VERSION 5.8 ;
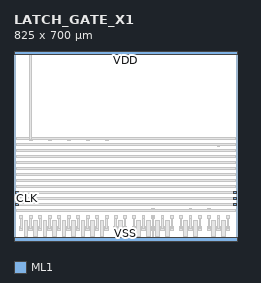
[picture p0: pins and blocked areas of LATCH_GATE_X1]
MACRO LATCH_GATE_X1
  CLASS CORE ;
  ORIGIN 0 0 ;
  SIZE 825 BY 700 ;
  SITE ICPS2023_5_ROW700 ;
  PIN D
    DIRECTION INPUT ;
    USE SIGNAL ;
    PORT
      LAYER ML1 ;
        RECT 5 130 15 140 ;
        RECT 810 130 820 140 ;
    END
  END D
  PIN CLK
    DIRECTION INPUT ;
    USE SIGNAL ;
    PORT
      LAYER ML1 ;
        RECT 5 152 15 162 ;
        RECT 810 152 820 162 ;
    END
  END CLK
  PIN Q
    DIRECTION OUTPUT ;
    USE SIGNAL ;
    PORT
      LAYER ML1 ;
        RECT 5 174 15 184 ;
        RECT 810 174 820 184 ;
    END
  END Q
  PIN VDD
    DIRECTION INOUT ;
    USE POWER ;
    PORT
      LAYER ML1 ;
        RECT 0 688 825 700 ;
    END
  END VDD
  PIN VSS
    DIRECTION INOUT ;
    USE GROUND ;
    PORT
      LAYER ML1 ;
        RECT 0 0 825 12 ;
    END
  END VSS
  OBS
    LAYER ML1 ;
      RECT 20 39.5 33 52.5 ;
      RECT 55 39.5 68 52.5 ;
      RECT 90 39.5 103 52.5 ;
      RECT 125 39.5 138 52.5 ;
      RECT 160 39.5 173 52.5 ;
      RECT 195 39.5 208 52.5 ;
      RECT 230 39.5 243 52.5 ;
      RECT 265 39.5 278 52.5 ;
      RECT 300 39.5 313 52.5 ;
      RECT 335 39.5 348 52.5 ;
      RECT 37.5 16 50.5 29 ;
      RECT 37.5 63 50.5 76 ;
      RECT 37 16 51 76 ;
      RECT 72.5 16 85.5 29 ;
      RECT 72.5 63 85.5 76 ;
      RECT 72 16 86 76 ;
      RECT 107.5 16 120.5 29 ;
      RECT 107.5 63 120.5 76 ;
      RECT 107 16 121 76 ;
      RECT 142.5 16 155.5 29 ;
      RECT 142.5 63 155.5 76 ;
      RECT 142 16 156 76 ;
      RECT 177.5 16 190.5 29 ;
      RECT 177.5 63 190.5 76 ;
      RECT 177 16 191 76 ;
      RECT 212.5 16 225.5 29 ;
      RECT 212.5 63 225.5 76 ;
      RECT 212 16 226 76 ;
      RECT 247.5 16 260.5 29 ;
      RECT 247.5 63 260.5 76 ;
      RECT 247 16 261 76 ;
      RECT 282.5 16 295.5 29 ;
      RECT 282.5 63 295.5 76 ;
      RECT 282 16 296 76 ;
      RECT 317.5 16 330.5 29 ;
      RECT 317.5 63 330.5 76 ;
      RECT 317 16 331 76 ;
      RECT 23.5 46 29.5 89 ;
      RECT 21.5 84 31.5 94 ;
      RECT 21.5 240 31.5 250 ;
      RECT 58.5 46 64.5 89 ;
      RECT 56.5 84 66.5 94 ;
      RECT 56.5 372 66.5 382 ;
      RECT 93.5 46 99.5 89 ;
      RECT 91.5 84 101.5 94 ;
      RECT 91.5 262 101.5 272 ;
      RECT 128.5 46 134.5 89 ;
      RECT 126.5 84 136.5 94 ;
      RECT 126.5 372 136.5 382 ;
      RECT 163.5 46 169.5 89 ;
      RECT 161.5 84 171.5 94 ;
      RECT 161.5 174 171.5 184 ;
      RECT 198.5 46 204.5 89 ;
      RECT 196.5 84 206.5 94 ;
      RECT 196.5 372 206.5 382 ;
      RECT 233.5 46 239.5 89 ;
      RECT 231.5 84 241.5 94 ;
      RECT 231.5 284 241.5 294 ;
      RECT 268.5 46 274.5 89 ;
      RECT 266.5 84 276.5 94 ;
      RECT 266.5 372 276.5 382 ;
      RECT 303.5 46 309.5 89 ;
      RECT 301.5 84 311.5 94 ;
      RECT 301.5 328 311.5 338 ;
      RECT 338.5 46 344.5 89 ;
      RECT 336.5 84 346.5 94 ;
      RECT 336.5 372 346.5 382 ;
      RECT 39 130 49 140 ;
      RECT 74 284 84 294 ;
      RECT 109 174 119 184 ;
      RECT 144 328 154 338 ;
      RECT 179 262 189 272 ;
      RECT 214 240 224 250 ;
      RECT 249 152 259 162 ;
      RECT 284 130 294 140 ;
      RECT 319 152 329 162 ;
      RECT 368 39.5 381 52.5 ;
      RECT 403 39.5 416 52.5 ;
      RECT 385.5 16 398.5 29 ;
      RECT 385.5 63 398.5 76 ;
      RECT 385 16 399 76 ;
      RECT 371.5 46 377.5 89 ;
      RECT 369.5 84 379.5 94 ;
      RECT 369.5 196 379.5 206 ;
      RECT 406.5 46 412.5 89 ;
      RECT 404.5 84 414.5 94 ;
      RECT 404.5 262 414.5 272 ;
      RECT 387 284 397 294 ;
      RECT 436 39.5 449 52.5 ;
      RECT 471 39.5 484 52.5 ;
      RECT 506 39.5 519 52.5 ;
      RECT 541 39.5 554 52.5 ;
      RECT 576 39.5 589 52.5 ;
      RECT 453.5 16 466.5 29 ;
      RECT 453.5 63 466.5 76 ;
      RECT 453 16 467 76 ;
      RECT 488.5 16 501.5 29 ;
      RECT 488.5 63 501.5 76 ;
      RECT 488 16 502 76 ;
      RECT 523.5 16 536.5 29 ;
      RECT 523.5 63 536.5 76 ;
      RECT 523 16 537 76 ;
      RECT 558.5 16 571.5 29 ;
      RECT 558.5 63 571.5 76 ;
      RECT 558 16 572 76 ;
      RECT 439.5 46 445.5 89 ;
      RECT 437.5 84 447.5 94 ;
      RECT 437.5 284 447.5 294 ;
      RECT 474.5 46 480.5 89 ;
      RECT 472.5 84 482.5 94 ;
      RECT 472.5 306 482.5 316 ;
      RECT 509.5 46 515.5 89 ;
      RECT 507.5 84 517.5 94 ;
      RECT 507.5 108 517.5 118 ;
      RECT 544.5 46 550.5 89 ;
      RECT 542.5 84 552.5 94 ;
      RECT 542.5 218 552.5 228 ;
      RECT 579.5 46 585.5 89 ;
      RECT 577.5 84 587.5 94 ;
      RECT 577.5 174 587.5 184 ;
      RECT 455 240 465 250 ;
      RECT 490 152 500 162 ;
      RECT 525 262 535 272 ;
      RECT 560 328 570 338 ;
      RECT 609 39.5 622 52.5 ;
      RECT 644 39.5 657 52.5 ;
      RECT 679 39.5 692 52.5 ;
      RECT 626.5 16 639.5 29 ;
      RECT 626.5 63 639.5 76 ;
      RECT 626 16 640 76 ;
      RECT 661.5 16 674.5 29 ;
      RECT 661.5 63 674.5 76 ;
      RECT 661 16 675 76 ;
      RECT 612.5 46 618.5 89 ;
      RECT 610.5 84 620.5 94 ;
      RECT 610.5 196 620.5 206 ;
      RECT 647.5 46 653.5 89 ;
      RECT 645.5 84 655.5 94 ;
      RECT 645.5 108 655.5 118 ;
      RECT 682.5 46 688.5 89 ;
      RECT 680.5 84 690.5 94 ;
      RECT 680.5 240 690.5 250 ;
      RECT 628 174 638 184 ;
      RECT 663 130 673 140 ;
      RECT 712 39.5 725 52.5 ;
      RECT 747 39.5 760 52.5 ;
      RECT 782 39.5 795 52.5 ;
      RECT 729.5 16 742.5 29 ;
      RECT 729.5 63 742.5 76 ;
      RECT 729 16 743 76 ;
      RECT 764.5 16 777.5 29 ;
      RECT 764.5 63 777.5 76 ;
      RECT 764 16 778 76 ;
      RECT 715.5 46 721.5 89 ;
      RECT 713.5 84 723.5 94 ;
      RECT 713.5 108 723.5 118 ;
      RECT 750.5 46 756.5 89 ;
      RECT 748.5 84 758.5 94 ;
      RECT 748.5 350 758.5 360 ;
      RECT 785.5 46 791.5 89 ;
      RECT 783.5 84 793.5 94 ;
      RECT 783.5 328 793.5 338 ;
      RECT 731 152 741 162 ;
      RECT 766 130 776 140 ;
      RECT 10 110 815 116 ;
      RECT 10 132 815 138 ;
      RECT 10 154 815 160 ;
      RECT 10 176 815 182 ;
      RECT 10 198 815 204 ;
      RECT 10 220 815 226 ;
      RECT 10 242 815 248 ;
      RECT 10 264 815 270 ;
      RECT 10 286 815 292 ;
      RECT 10 308 815 314 ;
      RECT 10 330 815 336 ;
      RECT 10 352 815 358 ;
      RECT 10 374 815 380 ;
      RECT 509.5 3 515.5 92 ;
      RECT 58.5 374 64.5 697 ;
  END
END LATCH_GATE_X1
